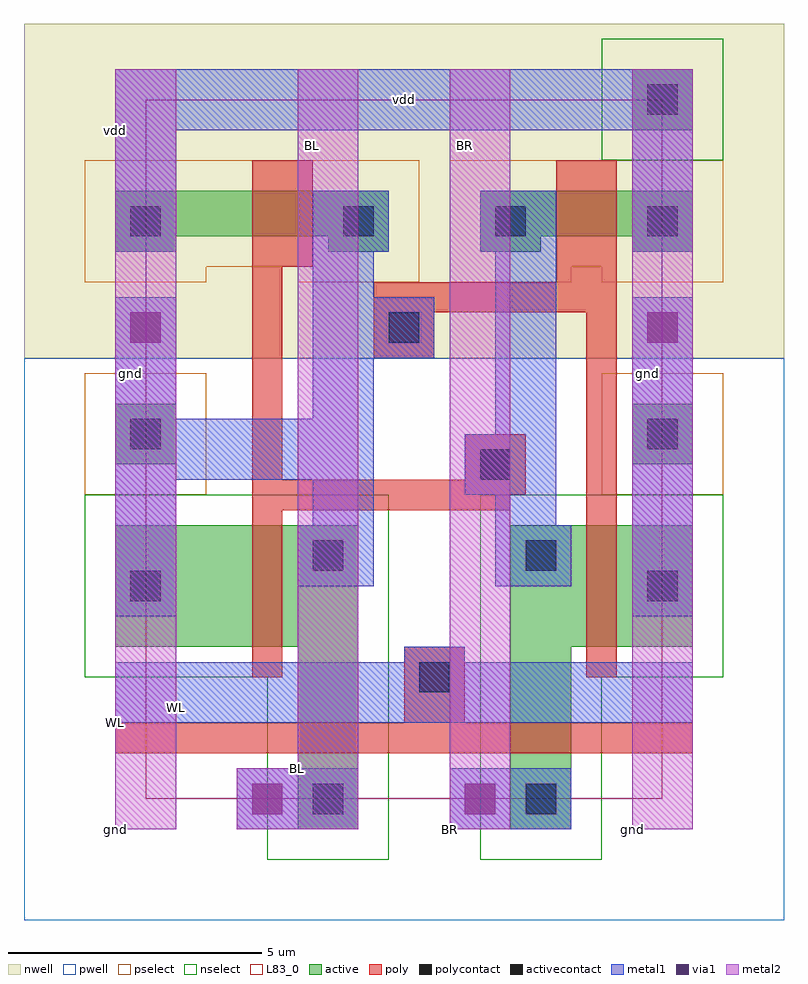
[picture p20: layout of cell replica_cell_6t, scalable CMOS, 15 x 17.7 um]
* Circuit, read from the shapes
.subckt replica_cell_6t BL BR WL gnd vdd
M1 gnd n1 gnd gnd nfet w=2.4u l=0.6u
M2 gnd WL BL gnd nfet w=1.2u l=0.6u
M3 n1 WL BR gnd nfet w=1.2u l=0.6u
M4 gnd gnd n1 gnd nfet w=2.4u l=0.6u
M5 gnd n1 vdd vdd pfet w=0.9u l=1.2u
M6 vdd gnd n1 vdd pfet w=0.9u l=1.2u
.ends

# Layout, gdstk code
import gdstk
lib = gdstk.Library(unit=1e-6, precision=1e-09)
def R(c, l, rs):  # rectangles x0, y0, x1, y1
    for r in rs: c.add(gdstk.rectangle(r[:2], r[2:], *l))
def A(c, l, x, y, w, h, nx, ny, dx, dy):  # array of equal rectangles
    R(c, l, [(x+i*dx, y+j*dy, x+i*dx+w, y+j*dy+h) for i in range(nx) for j in range(ny)])
pwell = (41, 0)
nwell = (42, 0)
active = (43, 0)
pselect = (44, 0)
nselect = (45, 0)
poly = (46, 0)
polycontact = (47, 0)
activecontact = (48, 0)
metal1 = (49, 0)
via1 = (50, 0)
metal2 = (51, 0)
L83_0 = (83, 0)

replica_cell_6t = lib.new_cell('replica_cell_6t')
R(replica_cell_6t, pwell, [(-2.4,-2.4,12.6,8.7)])
R(replica_cell_6t, nwell, [(-2.4,8.7,12.6,15.3)])
A(replica_cell_6t, active, 3.6, 10.8, 1.2, 0.3, 3, 1, 3, 0)
R(replica_cell_6t, active, [(3,-0.6,4.2,3), (7.2,-0.6,8.4,3), (-0.6,3,4.2,5.4), (7.2,3,10.8,5.4), (-0.6,6.6,0.6,7.8), (9.6,6.6,10.8,7.8), (-0.6,10.8,0.6,11.1), (-0.6,11.1,4.8,12), (6.6,11.1,10.8,12), (9.6,13.2,10.8,14.4)])
A(replica_cell_6t, pselect, 3, 10.2, 2.4, 0.3, 3, 1, 3, 0)
R(replica_cell_6t, pselect, [(-1.2,6,1.2,8.4), (9,6,11.4,8.4), (-1.2,10.2,1.2,10.5), (-1.2,10.5,5.4,12.6), (6,10.5,11.4,12.6)])
R(replica_cell_6t, nselect, [(2.4,-1.2,4.8,2.4), (6.6,-1.2,9,2.4), (-1.2,2.4,4.8,6), (6.6,2.4,11.4,6), (9,12.6,11.4,15)])
R(replica_cell_6t, poly, [(-0.6,0.9,10.8,1.5), (5.1,1.5,6.3,3), (2.1,2.4,2.7,5.7), (8.7,2.4,9.3,9.6), (2.1,5.7,7.2,6), (2.1,6,7.5,6.3), (2.1,6.3,2.7,10.5), (6.3,6.3,7.5,7.2), (4.5,8.7,5.7,9.6), (4.5,9.6,9.3,10.2), (8.1,10.2,9.3,12.6), (2.1,10.5,3.3,12.6)])
R(replica_cell_6t, polycontact, [(5.4,2.1,6,2.7), (6.6,6.3,7.2,6.9), (4.8,9,5.4,9.6)])
A(replica_cell_6t, activecontact, 3.9, 11.1, 0.6, 0.6, 3, 1, 3, 0)
R(replica_cell_6t, activecontact, [(3.3,-0.3,3.9,0.3), (7.5,-0.3,8.1,0.3), (-0.3,3.9,0.3,4.5), (9.9,3.9,10.5,4.5), (3.3,4.5,3.9,5.1), (7.5,4.5,8.1,5.1), (-0.3,6.9,0.3,7.5), (9.9,6.9,10.5,7.5), (-0.3,11.1,0.3,11.7), (9.9,13.5,10.5,14.1)])
R(replica_cell_6t, metal1, [(1.8,-0.6,4.2,0.6), (6,-0.6,8.4,0.6), (-0.6,1.5,10.8,2.7), (-0.6,1.5,10.8,2.7), (5.1,2.7,6.3,3), (-0.6,3.6,0.6,6.3), (9.6,3.6,10.8,9.9), (3,4.2,4.5,5.4), (6.9,4.2,8.4,5.4), (3.3,5.4,4.5,6.3), (6.9,5.4,8.1,6), (6.3,6,8.1,7.2), (-0.6,6.3,4.5,7.5), (6.9,7.2,8.1,10.8), (-0.6,7.5,0.6,9.9), (3.3,7.5,4.5,8.7), (3.3,8.7,5.7,9.9), (3.3,9.9,4.5,10.8), (-0.6,10.8,0.6,13.2), (3.3,10.8,4.8,12), (6.6,10.8,8.1,12), (9.6,10.8,10.8,13.2), (-0.6,13.2,10.8,14.4), (-0.6,13.2,10.8,14.4)])
R(replica_cell_6t, via1, [(2.1,-0.3,2.7,0.3), (6.3,-0.3,6.9,0.3), (-0.3,9,0.3,9.6), (9.9,9,10.5,9.6)])
R(replica_cell_6t, metal2, [(-0.6,-0.6,0.6,14.4), (-0.6,-0.6,0.6,14.4), (1.8,-0.6,4.2,0.6), (6,-0.6,7.2,14.4), (6,-0.6,7.2,14.4), (9.6,-0.6,10.8,14.4), (9.6,-0.6,10.8,14.4), (3,0.6,4.2,14.4), (3,0.6,4.2,14.4)])
R(replica_cell_6t, L83_0, [(0,0,10.2,13.8)])
replica_cell_6t.add(gdstk.Label('WL', (0.6,1.8), layer=49, texttype=0))
replica_cell_6t.add(gdstk.Label('gnd', (-0.3,8.4), layer=51, texttype=0))
replica_cell_6t.add(gdstk.Label('gnd', (9.9,8.4), layer=51, texttype=0))
replica_cell_6t.add(gdstk.Label('vdd', (5.1,13.8), layer=49, texttype=0))
replica_cell_6t.add(gdstk.Label('BL', (3.3,12.9), layer=51, texttype=0))
replica_cell_6t.add(gdstk.Label('BR', (6.3,12.9), layer=51, texttype=0))
replica_cell_6t.add(gdstk.Label('BL', (3,0.6), layer=51, texttype=0))
replica_cell_6t.add(gdstk.Label('WL', (-0.6,1.5), layer=49, texttype=0))
replica_cell_6t.add(gdstk.Label('gnd', (-0.6,-0.6), layer=51, texttype=0))
replica_cell_6t.add(gdstk.Label('gnd', (9.6,-0.6), layer=51, texttype=0))
replica_cell_6t.add(gdstk.Label('vdd', (-0.6,13.2), layer=49, texttype=0))
replica_cell_6t.add(gdstk.Label('BR', (6,-0.6), layer=51, texttype=0))

lib.write_gds('replica_cell_6t.gds')
